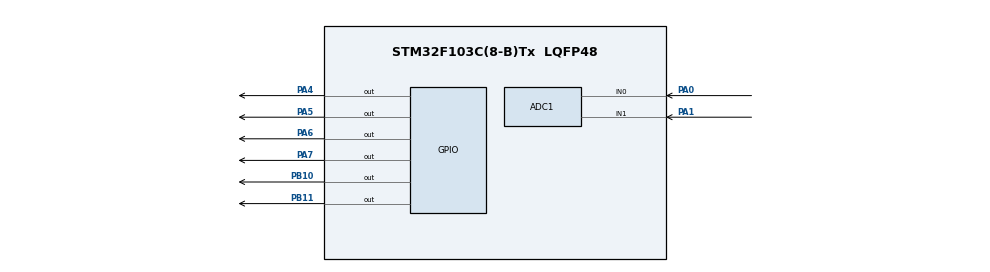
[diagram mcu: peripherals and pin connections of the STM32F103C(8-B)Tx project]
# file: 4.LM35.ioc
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ADC1.Channel-0\#ChannelRegularConversion=ADC_CHANNEL_0
ADC1.ContinuousConvMode=ENABLE
ADC1.NbrOfConversion=1
ADC1.NbrOfConversionFlag=1
ADC1.Rank-0\#ChannelRegularConversion=1
ADC1.SamplingTime-0\#ChannelRegularConversion=ADC_SAMPLETIME_13CYCLES_5
ADC1.master=1
Mcu.Family=STM32F1
Mcu.Name=STM32F103C(8-B)Tx
Mcu.Package=LQFP48
NVIC.PriorityGroup=NVIC_PRIORITYGROUP_4
PA0-WKUP.Signal=ADCx_IN0
PA1.Signal=ADCx_IN1
PA13.Mode=Serial_Wire
PA13.Signal=SYS_JTMS-SWDIO
PA14.Mode=Serial_Wire
PA14.Signal=SYS_JTCK-SWCLK
PA4.Signal=GPIO_Output
PA5.Signal=GPIO_Output
PA6.Signal=GPIO_Output
PA7.Signal=GPIO_Output
PB10.Signal=GPIO_Output
PB11.Signal=GPIO_Output
ProjectManager.HeapSize=0x200
ProjectManager.StackSize=0x400
ProjectManager.TargetToolchain=MDK-ARM V5.32
RCC.APB1Freq_Value=8000000
RCC.APB2Freq_Value=8000000
RCC.SYSCLKSource=RCC_SYSCLKSOURCE_PLLCLK
SH.ADCx_IN0.0=ADC1_IN0,IN0
SH.ADCx_IN1.0=ADC1_IN1,IN1
board=custom

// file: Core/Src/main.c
/* USER CODE BEGIN Header */
/**
  ******************************************************************************
  * @file           : main.c
  * @brief          : Main program body
  ******************************************************************************
  * @attention
  *
  * Copyright (c) 2023 STMicroelectronics.
  * All rights reserved.
  *
  * This software is licensed under terms that can be found in the LICENSE file
  * in the root directory of this software component.
  * If no LICENSE file comes with this software, it is provided AS-IS.
  *
  ******************************************************************************
  */
/* USER CODE END Header */
#include "main.h"
#include "tm_stm32_hd44780.h"
#include "stdio.h"

 ADC_HandleTypeDef hadc1;

void SystemClock_Config(void);
static void MX_GPIO_Init(void);
static void MX_ADC1_Init(void);

int main(void)
{
  /* USER CODE BEGIN 1 */
	char x[20];
	int adc_value;
	float temp;

  HAL_Init();
  SystemClock_Config();
  MX_GPIO_Init();
  MX_ADC1_Init();

  TM_HD44780_Init(16,2);
  TM_HD44780_Puts(0,0,"STM32");
  TM_HD44780_Puts(0,1,"BOOK");
  HAL_Delay(1000);
  TM_HD44780_Clear();

	HAL_ADC_Init(&hadc1);
	HAL_ADCEx_Calibration_Start(&hadc1);
	HAL_ADC_Start(&hadc1);

  while (1)
  {

		if(HAL_ADC_PollForConversion(&hadc1,100) == HAL_OK)
		{
		adc_value = HAL_ADC_GetValue(&hadc1);
		temp = (float)(adc_value * 3.3 / 4095.0) * 100.0;

		}
    sprintf(x,"TEMP:%2.2f",temp);
		TM_HD44780_Puts(0,0,x);
		HAL_Delay(300);

  }
}

void SystemClock_Config(void)
{
  RCC_OscInitTypeDef RCC_OscInitStruct = {0};
  RCC_ClkInitTypeDef RCC_ClkInitStruct = {0};
  RCC_PeriphCLKInitTypeDef PeriphClkInit = {0};

  /** Initializes the RCC Oscillators according to the specified parameters
  * in the RCC_OscInitTypeDef structure.
  */
  RCC_OscInitStruct.OscillatorType = RCC_OSCILLATORTYPE_HSI;
  RCC_OscInitStruct.HSIState = RCC_HSI_ON;
  RCC_OscInitStruct.HSICalibrationValue = RCC_HSICALIBRATION_DEFAULT;
  RCC_OscInitStruct.PLL.PLLState = RCC_PLL_NONE;
  if (HAL_RCC_OscConfig(&RCC_OscInitStruct) != HAL_OK)
  {
    Error_Handler();
  }

  /** Initializes the CPU, AHB and APB buses clocks
  */
  RCC_ClkInitStruct.ClockType = RCC_CLOCKTYPE_HCLK|RCC_CLOCKTYPE_SYSCLK
                              |RCC_CLOCKTYPE_PCLK1|RCC_CLOCKTYPE_PCLK2;
  RCC_ClkInitStruct.SYSCLKSource = RCC_SYSCLKSOURCE_HSI;
  RCC_ClkInitStruct.AHBCLKDivider = RCC_SYSCLK_DIV1;
  RCC_ClkInitStruct.APB1CLKDivider = RCC_HCLK_DIV2;
  RCC_ClkInitStruct.APB2CLKDivider = RCC_HCLK_DIV1;

  if (HAL_RCC_ClockConfig(&RCC_ClkInitStruct, FLASH_LATENCY_0) != HAL_OK)
  {
    Error_Handler();
  }
  PeriphClkInit.PeriphClockSelection = RCC_PERIPHCLK_ADC;
  PeriphClkInit.AdcClockSelection = RCC_ADCPCLK2_DIV2;
  if (HAL_RCCEx_PeriphCLKConfig(&PeriphClkInit) != HAL_OK)
  {
    Error_Handler();
  }
}

static void MX_ADC1_Init(void)
{

  ADC_ChannelConfTypeDef sConfig = {0};

  /** Common config
  */
  hadc1.Instance = ADC1;
  hadc1.Init.ScanConvMode = ADC_SCAN_DISABLE;
  hadc1.Init.ContinuousConvMode = ENABLE;
  hadc1.Init.DiscontinuousConvMode = DISABLE;
  hadc1.Init.ExternalTrigConv = ADC_SOFTWARE_START;
  hadc1.Init.DataAlign = ADC_DATAALIGN_RIGHT;
  hadc1.Init.NbrOfConversion = 1;
  if (HAL_ADC_Init(&hadc1) != HAL_OK)
  {
    Error_Handler();
  }

  /** Configure Regular Channel
  */
  sConfig.Channel = ADC_CHANNEL_1;
  sConfig.Rank = ADC_REGULAR_RANK_1;
  sConfig.SamplingTime = ADC_SAMPLETIME_239CYCLES_5;
  if (HAL_ADC_ConfigChannel(&hadc1, &sConfig) != HAL_OK)
  {
    Error_Handler();
  }

}

static void MX_GPIO_Init(void)
{
  GPIO_InitTypeDef GPIO_InitStruct = {0};

  /* GPIO Ports Clock Enable */
  __HAL_RCC_GPIOA_CLK_ENABLE();
  __HAL_RCC_GPIOB_CLK_ENABLE();

  /*Configure GPIO pin Output Level */
  HAL_GPIO_WritePin(GPIOA, GPIO_PIN_4|GPIO_PIN_5|GPIO_PIN_6|GPIO_PIN_7, GPIO_PIN_RESET);

  /*Configure GPIO pin Output Level */
  HAL_GPIO_WritePin(GPIOB, GPIO_PIN_10|GPIO_PIN_11, GPIO_PIN_RESET);

  /*Configure GPIO pins : PA4 PA5 PA6 PA7 */
  GPIO_InitStruct.Pin = GPIO_PIN_4|GPIO_PIN_5|GPIO_PIN_6|GPIO_PIN_7;
  GPIO_InitStruct.Mode = GPIO_MODE_OUTPUT_PP;
  GPIO_InitStruct.Pull = GPIO_NOPULL;
  GPIO_InitStruct.Speed = GPIO_SPEED_FREQ_LOW;
  HAL_GPIO_Init(GPIOA, &GPIO_InitStruct);

  /*Configure GPIO pins : PB10 PB11 */
  GPIO_InitStruct.Pin = GPIO_PIN_10|GPIO_PIN_11;
  GPIO_InitStruct.Mode = GPIO_MODE_OUTPUT_PP;
  GPIO_InitStruct.Pull = GPIO_NOPULL;
  GPIO_InitStruct.Speed = GPIO_SPEED_FREQ_LOW;
  HAL_GPIO_Init(GPIOB, &GPIO_InitStruct);

}

void Error_Handler(void)
{
  __disable_irq();
  while (1)
  {
  }
}
